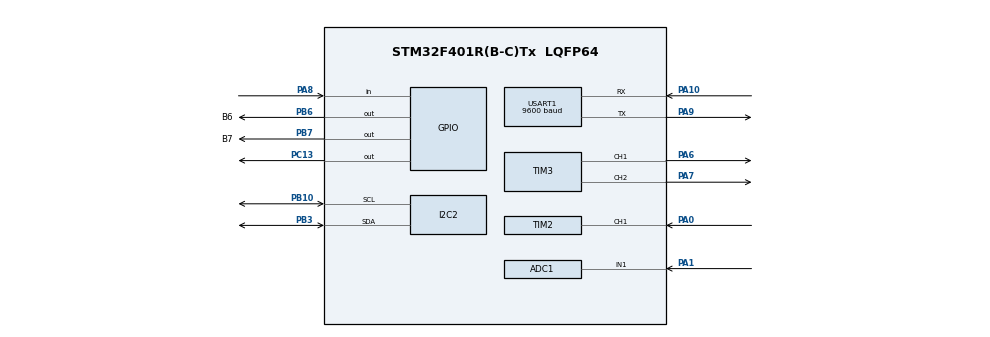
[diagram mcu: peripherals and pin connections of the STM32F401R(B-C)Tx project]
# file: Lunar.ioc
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ADC1.Channel-0\#ChannelRegularConversion=ADC_CHANNEL_1
ADC1.NbrOfConversionFlag=1
ADC1.Rank-0\#ChannelRegularConversion=1
ADC1.SamplingTime-0\#ChannelRegularConversion=ADC_SAMPLETIME_84CYCLES
ADC1.master=1
Mcu.Family=STM32F4
Mcu.Name=STM32F401R(B-C)Tx
Mcu.Package=LQFP64
NVIC.PriorityGroup=NVIC_PRIORITYGROUP_4
PA0-WKUP.Signal=S_TIM2_CH1_ETR
PA1.Signal=ADCx_IN1
PA10.Mode=Asynchronous
PA10.Signal=USART1_RX
PA13.Mode=Serial_Wire
PA13.Signal=SYS_JTMS-SWDIO
PA14.Mode=Serial_Wire
PA14.Signal=SYS_JTCK-SWCLK
PA6.Signal=S_TIM3_CH1
PA7.Signal=S_TIM3_CH2
PA8.Signal=GPIO_Input
PA9.Mode=Asynchronous
PA9.Signal=USART1_TX
PB10.Mode=I2C
PB10.Signal=I2C2_SCL
PB3.Mode=I2C
PB3.Signal=I2C2_SDA
PB6.GPIO_Label=B6
PB6.GPIO_ModeDefaultOutputPP=GPIO_MODE_OUTPUT_OD
PB6.GPIO_PuPd=GPIO_NOPULL
PB6.Signal=GPIO_Output
PB7.GPIO_Label=B7
PB7.GPIO_ModeDefaultOutputPP=GPIO_MODE_OUTPUT_OD
PB7.GPIO_PuPd=GPIO_NOPULL
PB7.Signal=GPIO_Output
PC13-ANTI_TAMP.Signal=GPIO_Output
ProjectManager.HeapSize=0x200
ProjectManager.StackSize=0x400
ProjectManager.TargetToolchain=MDK-ARM V5.32
RCC.AHBFreq_Value=16000000
RCC.APB1Freq_Value=16000000
RCC.APB2Freq_Value=16000000
RCC.CortexFreq_Value=16000000
RCC.HSE_VALUE=25000000
RCC.HSI_VALUE=16000000
RCC.LSE_VALUE=32768
RCC.SYSCLKFreq_VALUE=16000000
RCC.VCOOutputFreq_Value=192000000
SH.ADCx_IN1.0=ADC1_IN1,IN1
SH.S_TIM2_CH1_ETR.0=TIM2_CH1,TriggerSource_TI1FP1
SH.S_TIM3_CH1.0=TIM3_CH1,PWM Generation1 CH1
SH.S_TIM3_CH2.0=TIM3_CH2,PWM Generation2 CH2
TIM3.Channel-PWM\ Generation1\ CH1=TIM_CHANNEL_1
TIM3.Channel-PWM\ Generation2\ CH2=TIM_CHANNEL_2
USART1.BaudRate=9600
USART1.VirtualMode=VM_ASYNC
VP_TIM2_VS_ControllerModeClock.Mode=Clock Mode
VP_TIM3_VS_ClockSourceINT.Mode=Internal
board=custom

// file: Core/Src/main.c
/* USER CODE BEGIN Header */
/**
  ******************************************************************************
  * @file           : main.c
  * @brief          : Main program body
  ******************************************************************************
  * @attention
  *
  * Copyright (c) 2026 STMicroelectronics.
  * All rights reserved.
  *
  * This software is licensed under terms that can be found in the LICENSE file
  * in the root directory of this software component.
  * If no LICENSE file comes with this software, it is provided AS-IS.
  *
  ******************************************************************************
  */
/* USER CODE END Header */
#include "main.h"

/* USER CODE BEGIN Includes */
#include "OLED.h"
#include "Temprature.h"
#include "delay.h"
#include "MOTOR.h"
#include "PRESSURE.h"
#include "WATER.h"
#include "NETWORK.h"

/* USER CODE END Includes */

ADC_HandleTypeDef hadc1;

I2C_HandleTypeDef hi2c2;

TIM_HandleTypeDef htim2;
TIM_HandleTypeDef htim3;

UART_HandleTypeDef huart1;

/* USER CODE BEGIN PV */
float temperature_b6 = 0.0f;
float temperature_b7 = 0.0f;

DS18B20_Status temperature_b6_status;
DS18B20_Status temperature_b7_status;
/* USER CODE END PV */

void SystemClock_Config(void);
static void MX_GPIO_Init(void);
static void MX_I2C2_Init(void);
static void MX_TIM3_Init(void);
static void MX_ADC1_Init(void);
static void MX_TIM2_Init(void);
static void MX_USART1_UART_Init(void);
/* USER CODE BEGIN PFP */
static void Temperature_Task(void);
static void Pressure_Task(void);
static void Water_Task(void);
static void Pump_Task(void);

/* USER CODE END PFP */

/* USER CODE BEGIN 0 */

static int16_t Temperature_ToX10(float temperature)
{
    return (temperature >= 0.0f)
        ? (int16_t)(temperature * 10.0f + 0.5f)
        : (int16_t)(temperature * 10.0f - 0.5f);
}

static void OLED_ShowTemperatureField(
    uint8_t column,
    char sensor_id,
    DS18B20_Status status,
    float temperature)
{
    int32_t temperature_x10;
    uint32_t absolute_x10;

    OLED_ShowChar(1, column, 'T');
    OLED_ShowChar(1, column + 1U, sensor_id);
    OLED_ShowChar(1, column + 2U, ':');

    if (status == DS18B20_BUSY)
    {
        OLED_ShowString(1, column + 3U, "WAIT ");
        return;
    }
    if (status != DS18B20_OK)
    {
        OLED_ShowString(1, column + 3U, "ERR  ");
        return;
    }

    temperature_x10 = Temperature_ToX10(temperature);
    absolute_x10 = (temperature_x10 < 0)
        ? (uint32_t)(-temperature_x10)
        : (uint32_t)temperature_x10;
    if (absolute_x10 > 999U)
    {
        absolute_x10 = 999U;
    }

    OLED_ShowChar(1, column + 3U, temperature_x10 < 0 ? '-' : ' ');
    OLED_ShowNum(1, column + 4U, absolute_x10 / 10U, 2U);
    OLED_ShowChar(1, column + 6U, '.');
    OLED_ShowNum(1, column + 7U, absolute_x10 % 10U, 1U);
}

static void Temperature_Task(void)
{
    PERIODIC(750U);

    temperature_b6_status = DS18B20_ReadTemperature(
        B6_GPIO_Port, B6_Pin, &temperature_b6);
    temperature_b7_status = DS18B20_ReadTemperature(
        B7_GPIO_Port, B7_Pin, &temperature_b7);

    OLED_ShowTemperatureField(
        1U, '1', temperature_b6_status, temperature_b6);
    OLED_ShowTemperatureField(
        9U, '2', temperature_b7_status, temperature_b7);
}

static void Pressure_Task(void)
{
    int16_t delta_adc;
    uint16_t delta_magnitude;
    PRESSURE_Status pressure_status;

    PERIODIC(100U);

    pressure_status = PRESSURE_Update();

    if (pressure_status == PRESSURE_ADC_ERROR)
    {
        OLED_ShowString(3, 1, "Press:ADC ERROR ");
        OLED_ShowString(4, 1, "A:---- Z:");
        OLED_ShowNum(4, 10, PRESSURE_GetZeroADC(), 4U);
        return;
    }
    if (pressure_status != PRESSURE_OK)
    {
        OLED_ShowString(3, 1, "Press:WAIT      ");
        return;
    }

    /* Show Pa directly so changes below 0.001 MPa are still visible. */
    OLED_ShowString(3, 1, "P:");
    OLED_ShowNum(3, 3, PRESSURE_GetPa(), 7U);
    OLED_ShowString(3, 10, " Pa    ");

    delta_adc = PRESSURE_GetDeltaADC();
    delta_magnitude = (delta_adc < 0)
        ? (uint16_t)(-delta_adc)
        : (uint16_t)delta_adc;
    OLED_ShowString(4, 1, "A:");
    OLED_ShowNum(4, 3, PRESSURE_GetRawADC(), 4U);
    OLED_ShowString(4, 7, " D:");
    OLED_ShowChar(4, 10, delta_adc < 0 ? '-' : '+');
    OLED_ShowNum(4, 11, delta_magnitude, 4U);
    OLED_ShowString(4, 15, "  ");
}

static void Water_Task(void)
{
    uint16_t flow_x100;
    WATER_Status water_status;

    PERIODIC(100U);

    water_status = WATER_Update();

    if (water_status == WATER_TIMER_ERROR)
    {
        OLED_ShowString(2, 1, "Flow:TIM ERROR  ");
        return;
    }
    if (water_status != WATER_OK)
    {
        OLED_ShowString(2, 1, "Flow:WAIT       ");
        return;
    }

    flow_x100 = WATER_GetFlowCentiLMin();

    OLED_ShowString(2, 1, "Flow:");
    OLED_ShowNum(2, 6, flow_x100 / 100U, 2);
    OLED_ShowChar(2, 8, '.');
    OLED_ShowNum(2, 9, flow_x100 % 100U, 2);
    OLED_ShowString(2, 11, " L/min");
}

static void Pump_Task(void)
{
    static uint8_t pump_duty_percent = 0U;
    static uint32_t pump_duration_ms = 0U;
    NETWORK_PumpCommand command;
    NETWORK_CommandStatus command_status;

    command_status = NETWORK_ReadPumpCommand(&command);

    if (command_status == NETWORK_COMMAND_VALID)
    {
        MOTOR_SliceReset();
        pump_duty_percent = command.duty_percent;
        pump_duration_ms = command.duration_ms;

        if (pump_duty_percent > 0U)
        {
            (void)MOTOR_Slice(
                pump_duty_percent,
                pump_duration_ms);
        }

        (void)NETWORK_SendPumpAck(
            pump_duty_percent,
            pump_duration_ms,
            1U);
    }
    else if (command_status == NETWORK_COMMAND_INVALID)
    {
        (void)NETWORK_SendPumpAck(0U, 0U, 0U);
    }

    if (MOTOR_GetSliceStatus() == MOTOR_SLICE_RUNNING)
    {
        (void)MOTOR_Slice(
            pump_duty_percent,
            pump_duration_ms);
    }
}

/* USER CODE END 0 */

int main(void)
{

  /* MCU Configuration--------------------------------------------------------*/

  /* Reset of all peripherals, Initializes the Flash interface and the Systick. */
  HAL_Init();

  /* Configure the system clock */
  SystemClock_Config();

  /* Initialize all configured peripherals */
  MX_GPIO_Init();
  MX_I2C2_Init();
  MX_TIM3_Init();
  MX_ADC1_Init();
  MX_TIM2_Init();
  MX_USART1_UART_Init();
  /* USER CODE BEGIN 2 */
    OLED_Init();

	DS18B20_Init();
	Delay_Init();
	MOTOR_Init();
	PRESSURE_Init();
	WATER_Init();
	NETWORK_Init(&huart1);

    OLED_ShowString(1, 1, "T1:WAIT T2:WAIT ");
    OLED_ShowString(2, 1, "Flow:WAIT       ");
    OLED_ShowString(3, 1, "Press:WAIT      ");
    OLED_ShowString(4, 1, "A:---- D:-----  ");

  /* USER CODE END 2 */

  /* Infinite loop */
  /* USER CODE BEGIN WHILE */
  while (1)
  {
    Temperature_Task();
	Pressure_Task();
	Water_Task();
	Pump_Task();

	PERIODIC_START(network_send, 250U)
        NETWORK_SensorFrame frame;

        frame.temperature_1_x10 = Temperature_ToX10(temperature_b6);
        frame.temperature_1_status = (uint8_t)temperature_b6_status;
        frame.temperature_2_x10 = Temperature_ToX10(temperature_b7);
        frame.temperature_2_status = (uint8_t)temperature_b7_status;
        frame.flow_centi_l_min = WATER_GetFlowCentiLMin();
        frame.flow_status = (uint8_t)WATER_GetStatus();
        frame.pressure_pa = PRESSURE_GetPa();
        frame.pressure_status = (uint8_t)PRESSURE_GetStatus();
        frame.pressure_adc = PRESSURE_GetRawADC();
        frame.pressure_delta_adc = PRESSURE_GetDeltaADC();
        frame.pump_duty_percent = MOTOR_GetDuty();
        frame.pump_status = (uint8_t)MOTOR_GetSliceStatus();
        frame.pump_remaining_ms = MOTOR_GetRemainingMs();

        (void)NETWORK_SendSensorData(&frame);

    PERIODIC_END;

    /* USER CODE END WHILE */

  }
}

void SystemClock_Config(void)
{
  RCC_OscInitTypeDef RCC_OscInitStruct = {0};
  RCC_ClkInitTypeDef RCC_ClkInitStruct = {0};

  /** Configure the main internal regulator output voltage
  */
  __HAL_RCC_PWR_CLK_ENABLE();
  __HAL_PWR_VOLTAGESCALING_CONFIG(PWR_REGULATOR_VOLTAGE_SCALE2);

  /** Initializes the RCC Oscillators according to the specified parameters
  * in the RCC_OscInitTypeDef structure.
  */
  RCC_OscInitStruct.OscillatorType = RCC_OSCILLATORTYPE_HSI;
  RCC_OscInitStruct.HSIState = RCC_HSI_ON;
  RCC_OscInitStruct.HSICalibrationValue = RCC_HSICALIBRATION_DEFAULT;
  RCC_OscInitStruct.PLL.PLLState = RCC_PLL_ON;
  RCC_OscInitStruct.PLL.PLLSource = RCC_PLLSOURCE_HSI;
  RCC_OscInitStruct.PLL.PLLM = 8;
  RCC_OscInitStruct.PLL.PLLN = 84;
  RCC_OscInitStruct.PLL.PLLP = RCC_PLLP_DIV2;
  RCC_OscInitStruct.PLL.PLLQ = 4;
  if (HAL_RCC_OscConfig(&RCC_OscInitStruct) != HAL_OK)
  {
    Error_Handler();
  }

  /** Initializes the CPU, AHB and APB buses clocks
  */
  RCC_ClkInitStruct.ClockType = RCC_CLOCKTYPE_HCLK|RCC_CLOCKTYPE_SYSCLK
                              |RCC_CLOCKTYPE_PCLK1|RCC_CLOCKTYPE_PCLK2;
  RCC_ClkInitStruct.SYSCLKSource = RCC_SYSCLKSOURCE_PLLCLK;
  RCC_ClkInitStruct.AHBCLKDivider = RCC_SYSCLK_DIV1;
  RCC_ClkInitStruct.APB1CLKDivider = RCC_HCLK_DIV2;
  RCC_ClkInitStruct.APB2CLKDivider = RCC_HCLK_DIV1;

  if (HAL_RCC_ClockConfig(&RCC_ClkInitStruct, FLASH_LATENCY_2) != HAL_OK)
  {
    Error_Handler();
  }
}

static void MX_ADC1_Init(void)
{

  ADC_ChannelConfTypeDef sConfig = {0};

  /** Configure the global features of the ADC (Clock, Resolution, Data Alignment and number of conversion)
  */
  hadc1.Instance = ADC1;
  hadc1.Init.ClockPrescaler = ADC_CLOCK_SYNC_PCLK_DIV4;
  hadc1.Init.Resolution = ADC_RESOLUTION_12B;
  hadc1.Init.ScanConvMode = DISABLE;
  hadc1.Init.ContinuousConvMode = DISABLE;
  hadc1.Init.DiscontinuousConvMode = DISABLE;
  hadc1.Init.ExternalTrigConvEdge = ADC_EXTERNALTRIGCONVEDGE_NONE;
  hadc1.Init.ExternalTrigConv = ADC_SOFTWARE_START;
  hadc1.Init.DataAlign = ADC_DATAALIGN_RIGHT;
  hadc1.Init.NbrOfConversion = 1;
  hadc1.Init.DMAContinuousRequests = DISABLE;
  hadc1.Init.EOCSelection = ADC_EOC_SINGLE_CONV;
  if (HAL_ADC_Init(&hadc1) != HAL_OK)
  {
    Error_Handler();
  }

  /** Configure for the selected ADC regular channel its corresponding rank in the sequencer and its sample time.
  */
  sConfig.Channel = ADC_CHANNEL_1;
  sConfig.Rank = 1;
  sConfig.SamplingTime = ADC_SAMPLETIME_84CYCLES;
  if (HAL_ADC_ConfigChannel(&hadc1, &sConfig) != HAL_OK)
  {
    Error_Handler();
  }

}

static void MX_I2C2_Init(void)
{

  hi2c2.Instance = I2C2;
  hi2c2.Init.ClockSpeed = 100000;
  hi2c2.Init.DutyCycle = I2C_DUTYCYCLE_2;
  hi2c2.Init.OwnAddress1 = 0;
  hi2c2.Init.AddressingMode = I2C_ADDRESSINGMODE_7BIT;
  hi2c2.Init.DualAddressMode = I2C_DUALADDRESS_DISABLE;
  hi2c2.Init.OwnAddress2 = 0;
  hi2c2.Init.GeneralCallMode = I2C_GENERALCALL_DISABLE;
  hi2c2.Init.NoStretchMode = I2C_NOSTRETCH_DISABLE;
  if (HAL_I2C_Init(&hi2c2) != HAL_OK)
  {
    Error_Handler();
  }

}

static void MX_TIM2_Init(void)
{

  TIM_SlaveConfigTypeDef sSlaveConfig = {0};
  TIM_MasterConfigTypeDef sMasterConfig = {0};

  htim2.Instance = TIM2;
  htim2.Init.Prescaler = 0;
  htim2.Init.CounterMode = TIM_COUNTERMODE_UP;
  htim2.Init.Period = 4294967295;
  htim2.Init.ClockDivision = TIM_CLOCKDIVISION_DIV1;
  htim2.Init.AutoReloadPreload = TIM_AUTORELOAD_PRELOAD_DISABLE;
  if (HAL_TIM_Base_Init(&htim2) != HAL_OK)
  {
    Error_Handler();
  }
  sSlaveConfig.SlaveMode = TIM_SLAVEMODE_EXTERNAL1;
  sSlaveConfig.InputTrigger = TIM_TS_TI1FP1;
  sSlaveConfig.TriggerPolarity = TIM_TRIGGERPOLARITY_RISING;
  sSlaveConfig.TriggerFilter = 4;
  if (HAL_TIM_SlaveConfigSynchro(&htim2, &sSlaveConfig) != HAL_OK)
  {
    Error_Handler();
  }
  sMasterConfig.MasterOutputTrigger = TIM_TRGO_RESET;
  sMasterConfig.MasterSlaveMode = TIM_MASTERSLAVEMODE_DISABLE;
  if (HAL_TIMEx_MasterConfigSynchronization(&htim2, &sMasterConfig) != HAL_OK)
  {
    Error_Handler();
  }

}

static void MX_TIM3_Init(void)
{

  TIM_ClockConfigTypeDef sClockSourceConfig = {0};
  TIM_MasterConfigTypeDef sMasterConfig = {0};
  TIM_OC_InitTypeDef sConfigOC = {0};

  htim3.Instance = TIM3;
  htim3.Init.Prescaler = 5;
  htim3.Init.CounterMode = TIM_COUNTERMODE_UP;
  htim3.Init.Period = 57343;
  htim3.Init.ClockDivision = TIM_CLOCKDIVISION_DIV1;
  htim3.Init.AutoReloadPreload = TIM_AUTORELOAD_PRELOAD_DISABLE;
  if (HAL_TIM_Base_Init(&htim3) != HAL_OK)
  {
    Error_Handler();
  }
  sClockSourceConfig.ClockSource = TIM_CLOCKSOURCE_INTERNAL;
  if (HAL_TIM_ConfigClockSource(&htim3, &sClockSourceConfig) != HAL_OK)
  {
    Error_Handler();
  }
  if (HAL_TIM_PWM_Init(&htim3) != HAL_OK)
  {
    Error_Handler();
  }
  sMasterConfig.MasterOutputTrigger = TIM_TRGO_RESET;
  sMasterConfig.MasterSlaveMode = TIM_MASTERSLAVEMODE_DISABLE;
  if (HAL_TIMEx_MasterConfigSynchronization(&htim3, &sMasterConfig) != HAL_OK)
  {
    Error_Handler();
  }
  sConfigOC.OCMode = TIM_OCMODE_PWM1;
  sConfigOC.Pulse = 0;
  sConfigOC.OCPolarity = TIM_OCPOLARITY_HIGH;
  sConfigOC.OCFastMode = TIM_OCFAST_DISABLE;
  if (HAL_TIM_PWM_ConfigChannel(&htim3, &sConfigOC, TIM_CHANNEL_1) != HAL_OK)
  {
    Error_Handler();
  }
  HAL_TIM_MspPostInit(&htim3);

}

static void MX_USART1_UART_Init(void)
{

  huart1.Instance = USART1;
  huart1.Init.BaudRate = 9600;
  huart1.Init.WordLength = UART_WORDLENGTH_8B;
  huart1.Init.StopBits = UART_STOPBITS_1;
  huart1.Init.Parity = UART_PARITY_NONE;
  huart1.Init.Mode = UART_MODE_TX_RX;
  huart1.Init.HwFlowCtl = UART_HWCONTROL_NONE;
  huart1.Init.OverSampling = UART_OVERSAMPLING_16;
  if (HAL_UART_Init(&huart1) != HAL_OK)
  {
    Error_Handler();
  }

}

static void MX_GPIO_Init(void)
{
  GPIO_InitTypeDef GPIO_InitStruct = {0};

  /* GPIO Ports Clock Enable */
  __HAL_RCC_GPIOC_CLK_ENABLE();
  __HAL_RCC_GPIOA_CLK_ENABLE();
  __HAL_RCC_GPIOB_CLK_ENABLE();

  /*Configure GPIO pin Output Level */
  HAL_GPIO_WritePin(GPIOC, GPIO_PIN_13, GPIO_PIN_RESET);

  /*Configure GPIO pin Output Level */
  HAL_GPIO_WritePin(GPIOA, GPIO_PIN_7, GPIO_PIN_RESET);

  /*Configure GPIO pin Output Level */
  HAL_GPIO_WritePin(GPIOB, B6_Pin|B7_Pin, GPIO_PIN_RESET);

  /*Configure GPIO pin : PC13 */
  GPIO_InitStruct.Pin = GPIO_PIN_13;
  GPIO_InitStruct.Mode = GPIO_MODE_OUTPUT_PP;
  GPIO_InitStruct.Pull = GPIO_NOPULL;
  GPIO_InitStruct.Speed = GPIO_SPEED_FREQ_LOW;
  HAL_GPIO_Init(GPIOC, &GPIO_InitStruct);

  /*Configure GPIO pin : PA8 */
  GPIO_InitStruct.Pin = GPIO_PIN_8;
  GPIO_InitStruct.Mode = GPIO_MODE_INPUT;
  GPIO_InitStruct.Pull = GPIO_NOPULL;
  HAL_GPIO_Init(GPIOA, &GPIO_InitStruct);

  /*Configure GPIO pin : PA7 (DRV8870 IN2, fixed low) */
  GPIO_InitStruct.Pin = GPIO_PIN_7;
  GPIO_InitStruct.Mode = GPIO_MODE_OUTPUT_PP;
  GPIO_InitStruct.Pull = GPIO_NOPULL;
  GPIO_InitStruct.Speed = GPIO_SPEED_FREQ_LOW;
  HAL_GPIO_Init(GPIOA, &GPIO_InitStruct);

  /*Configure GPIO pins : B6_Pin B7_Pin */
  GPIO_InitStruct.Pin = B6_Pin|B7_Pin;
  GPIO_InitStruct.Mode = GPIO_MODE_OUTPUT_OD;
  GPIO_InitStruct.Pull = GPIO_NOPULL;
  GPIO_InitStruct.Speed = GPIO_SPEED_FREQ_LOW;
  HAL_GPIO_Init(GPIOB, &GPIO_InitStruct);

}

void Error_Handler(void)
{
  __disable_irq();
  while (1)
  {
  }
}
